VERSION 5.7 ;
  NOWIREEXTENSIONATPIN ON ;
  DIVIDERCHAR "/" ;
  BUSBITCHARS "[]" ;
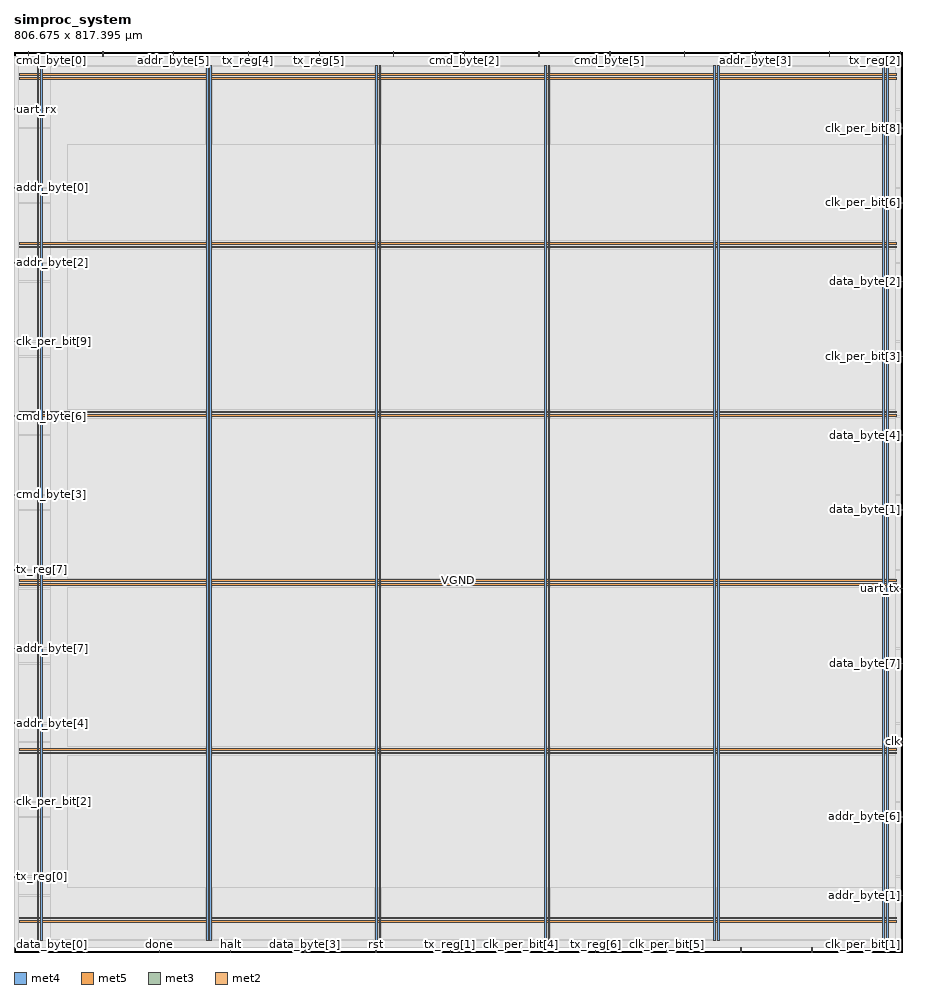
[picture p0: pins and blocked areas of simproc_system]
MACRO simproc_system
  CLASS BLOCK ;
  FOREIGN simproc_system ;
  ORIGIN 0.000 0.000 ;
  SIZE 806.675 BY 817.395 ;
  PIN VGND
    DIRECTION INOUT ;
    USE GROUND ;
    PORT
      LAYER met4 ;
        RECT 24.340 10.640 25.940 805.360 ;
    END
    PORT
      LAYER met4 ;
        RECT 177.940 10.640 179.540 805.360 ;
    END
    PORT
      LAYER met4 ;
        RECT 331.540 10.640 333.140 805.360 ;
    END
    PORT
      LAYER met4 ;
        RECT 485.140 10.640 486.740 805.360 ;
    END
    PORT
      LAYER met4 ;
        RECT 638.740 10.640 640.340 805.360 ;
    END
    PORT
      LAYER met4 ;
        RECT 792.340 10.640 793.940 805.360 ;
    END
    PORT
      LAYER met5 ;
        RECT 5.280 30.030 801.100 31.630 ;
    END
    PORT
      LAYER met5 ;
        RECT 5.280 183.210 801.100 184.810 ;
    END
    PORT
      LAYER met5 ;
        RECT 5.280 336.390 801.100 337.990 ;
    END
    PORT
      LAYER met5 ;
        RECT 5.280 489.570 801.100 491.170 ;
    END
    PORT
      LAYER met5 ;
        RECT 5.280 642.750 801.100 644.350 ;
    END
    PORT
      LAYER met5 ;
        RECT 5.280 795.930 801.100 797.530 ;
    END
  END VGND
  PIN VPWR
    DIRECTION INOUT ;
    USE POWER ;
    PORT
      LAYER met4 ;
        RECT 21.040 10.640 22.640 805.360 ;
    END
    PORT
      LAYER met4 ;
        RECT 174.640 10.640 176.240 805.360 ;
    END
    PORT
      LAYER met4 ;
        RECT 328.240 10.640 329.840 805.360 ;
    END
    PORT
      LAYER met4 ;
        RECT 481.840 10.640 483.440 805.360 ;
    END
    PORT
      LAYER met4 ;
        RECT 635.440 10.640 637.040 805.360 ;
    END
    PORT
      LAYER met4 ;
        RECT 789.040 10.640 790.640 805.360 ;
    END
    PORT
      LAYER met5 ;
        RECT 5.280 26.730 801.100 28.330 ;
    END
    PORT
      LAYER met5 ;
        RECT 5.280 179.910 801.100 181.510 ;
    END
    PORT
      LAYER met5 ;
        RECT 5.280 333.090 801.100 334.690 ;
    END
    PORT
      LAYER met5 ;
        RECT 5.280 486.270 801.100 487.870 ;
    END
    PORT
      LAYER met5 ;
        RECT 5.280 639.450 801.100 641.050 ;
    END
    PORT
      LAYER met5 ;
        RECT 5.280 792.630 801.100 794.230 ;
    END
  END VPWR
  PIN addr_byte[0]
    DIRECTION OUTPUT TRISTATE ;
    USE SIGNAL ;
    ANTENNADIFFAREA 0.795200 ;
    PORT
      LAYER met3 ;
        RECT 0.000 693.640 4.000 694.240 ;
    END
  END addr_byte[0]
  PIN addr_byte[1]
    DIRECTION OUTPUT TRISTATE ;
    USE SIGNAL ;
    ANTENNADIFFAREA 0.445500 ;
    PORT
      LAYER met3 ;
        RECT 802.675 51.040 806.675 51.640 ;
    END
  END addr_byte[1]
  PIN addr_byte[2]
    DIRECTION OUTPUT TRISTATE ;
    USE SIGNAL ;
    ANTENNADIFFAREA 0.795200 ;
    PORT
      LAYER met3 ;
        RECT 0.000 625.640 4.000 626.240 ;
    END
  END addr_byte[2]
  PIN addr_byte[3]
    DIRECTION OUTPUT TRISTATE ;
    USE SIGNAL ;
    ANTENNADIFFAREA 0.795200 ;
    PORT
      LAYER met2 ;
        RECT 673.070 813.395 673.350 817.395 ;
    END
  END addr_byte[3]
  PIN addr_byte[4]
    DIRECTION OUTPUT TRISTATE ;
    USE SIGNAL ;
    ANTENNADIFFAREA 0.795200 ;
    PORT
      LAYER met3 ;
        RECT 0.000 207.440 4.000 208.040 ;
    END
  END addr_byte[4]
  PIN addr_byte[5]
    DIRECTION OUTPUT TRISTATE ;
    USE SIGNAL ;
    ANTENNADIFFAREA 0.795200 ;
    PORT
      LAYER met2 ;
        RECT 144.990 813.395 145.270 817.395 ;
    END
  END addr_byte[5]
  PIN addr_byte[6]
    DIRECTION OUTPUT TRISTATE ;
    USE SIGNAL ;
    ANTENNADIFFAREA 0.795200 ;
    PORT
      LAYER met3 ;
        RECT 802.675 122.440 806.675 123.040 ;
    END
  END addr_byte[6]
  PIN addr_byte[7]
    DIRECTION OUTPUT TRISTATE ;
    USE SIGNAL ;
    ANTENNADIFFAREA 0.795200 ;
    PORT
      LAYER met3 ;
        RECT 0.000 275.440 4.000 276.040 ;
    END
  END addr_byte[7]
  PIN clk
    DIRECTION INPUT ;
    USE SIGNAL ;
    ANTENNAGATEAREA 0.852000 ;
    PORT
      LAYER met3 ;
        RECT 802.675 190.440 806.675 191.040 ;
    END
  END clk
  PIN clk_per_bit[0]
    DIRECTION INPUT ;
    USE SIGNAL ;
    ANTENNAGATEAREA 0.426000 ;
    PORT
      LAYER met2 ;
        RECT 80.590 813.395 80.870 817.395 ;
    END
  END clk_per_bit[0]
  PIN clk_per_bit[1]
    DIRECTION INPUT ;
    USE SIGNAL ;
    ANTENNAGATEAREA 0.742500 ;
    PORT
      LAYER met2 ;
        RECT 792.210 0.000 792.490 4.000 ;
    END
  END clk_per_bit[1]
  PIN clk_per_bit[2]
    DIRECTION INPUT ;
    USE SIGNAL ;
    ANTENNAGATEAREA 0.213000 ;
    PORT
      LAYER met3 ;
        RECT 0.000 136.040 4.000 136.640 ;
    END
  END clk_per_bit[2]
  PIN clk_per_bit[3]
    DIRECTION INPUT ;
    USE SIGNAL ;
    ANTENNAGATEAREA 0.852000 ;
    PORT
      LAYER met3 ;
        RECT 802.675 540.640 806.675 541.240 ;
    END
  END clk_per_bit[3]
  PIN clk_per_bit[4]
    DIRECTION INPUT ;
    USE SIGNAL ;
    ANTENNAGATEAREA 0.426000 ;
    PORT
      LAYER met2 ;
        RECT 460.550 0.000 460.830 4.000 ;
    END
  END clk_per_bit[4]
  PIN clk_per_bit[5]
    DIRECTION INPUT ;
    USE SIGNAL ;
    ANTENNAGATEAREA 0.426000 ;
    PORT
      LAYER met2 ;
        RECT 592.570 0.000 592.850 4.000 ;
    END
  END clk_per_bit[5]
  PIN clk_per_bit[6]
    DIRECTION INPUT ;
    USE SIGNAL ;
    ANTENNAGATEAREA 0.742500 ;
    PORT
      LAYER met3 ;
        RECT 802.675 680.040 806.675 680.640 ;
    END
  END clk_per_bit[6]
  PIN clk_per_bit[7]
    DIRECTION INPUT ;
    USE SIGNAL ;
    ANTENNAGATEAREA 0.742500 ;
    PORT
      LAYER met2 ;
        RECT 660.190 0.000 660.470 4.000 ;
    END
  END clk_per_bit[7]
  PIN clk_per_bit[8]
    DIRECTION INPUT ;
    USE SIGNAL ;
    ANTENNAGATEAREA 0.742500 ;
    PORT
      LAYER met3 ;
        RECT 802.675 748.040 806.675 748.640 ;
    END
  END clk_per_bit[8]
  PIN clk_per_bit[9]
    DIRECTION INPUT ;
    USE SIGNAL ;
    ANTENNAGATEAREA 0.213000 ;
    PORT
      LAYER met3 ;
        RECT 0.000 554.240 4.000 554.840 ;
    END
  END clk_per_bit[9]
  PIN cmd_byte[0]
    DIRECTION OUTPUT TRISTATE ;
    USE SIGNAL ;
    ANTENNADIFFAREA 0.795200 ;
    PORT
      LAYER met2 ;
        RECT 12.970 813.395 13.250 817.395 ;
    END
  END cmd_byte[0]
  PIN cmd_byte[1]
    DIRECTION OUTPUT TRISTATE ;
    USE SIGNAL ;
    ANTENNADIFFAREA 0.795200 ;
    PORT
      LAYER met2 ;
        RECT 608.670 813.395 608.950 817.395 ;
    END
  END cmd_byte[1]
  PIN cmd_byte[2]
    DIRECTION OUTPUT TRISTATE ;
    USE SIGNAL ;
    ANTENNADIFFAREA 0.795200 ;
    PORT
      LAYER met2 ;
        RECT 409.030 813.395 409.310 817.395 ;
    END
  END cmd_byte[2]
  PIN cmd_byte[3]
    DIRECTION OUTPUT TRISTATE ;
    USE SIGNAL ;
    ANTENNADIFFAREA 0.795200 ;
    PORT
      LAYER met3 ;
        RECT 0.000 414.840 4.000 415.440 ;
    END
  END cmd_byte[3]
  PIN cmd_byte[4]
    DIRECTION OUTPUT TRISTATE ;
    USE SIGNAL ;
    ANTENNADIFFAREA 0.795200 ;
    PORT
      LAYER met2 ;
        RECT 344.630 813.395 344.910 817.395 ;
    END
  END cmd_byte[4]
  PIN cmd_byte[5]
    DIRECTION OUTPUT TRISTATE ;
    USE SIGNAL ;
    ANTENNADIFFAREA 0.795200 ;
    PORT
      LAYER met2 ;
        RECT 541.050 813.395 541.330 817.395 ;
    END
  END cmd_byte[5]
  PIN cmd_byte[6]
    DIRECTION OUTPUT TRISTATE ;
    USE SIGNAL ;
    ANTENNADIFFAREA 0.795200 ;
    PORT
      LAYER met3 ;
        RECT 0.000 486.240 4.000 486.840 ;
    END
  END cmd_byte[6]
  PIN cmd_byte[7]
    DIRECTION OUTPUT TRISTATE ;
    USE SIGNAL ;
    ANTENNADIFFAREA 0.795200 ;
    PORT
      LAYER met2 ;
        RECT 64.490 0.000 64.770 4.000 ;
    END
  END cmd_byte[7]
  PIN data_byte[0]
    DIRECTION OUTPUT TRISTATE ;
    USE SIGNAL ;
    ANTENNADIFFAREA 0.795200 ;
    PORT
      LAYER met2 ;
        RECT 0.090 0.000 0.370 4.000 ;
    END
  END data_byte[0]
  PIN data_byte[1]
    DIRECTION OUTPUT TRISTATE ;
    USE SIGNAL ;
    ANTENNADIFFAREA 0.445500 ;
    PORT
      LAYER met3 ;
        RECT 802.675 401.240 806.675 401.840 ;
    END
  END data_byte[1]
  PIN data_byte[2]
    DIRECTION OUTPUT TRISTATE ;
    USE SIGNAL ;
    ANTENNADIFFAREA 0.445500 ;
    PORT
      LAYER met3 ;
        RECT 802.675 608.640 806.675 609.240 ;
    END
  END data_byte[2]
  PIN data_byte[3]
    DIRECTION OUTPUT TRISTATE ;
    USE SIGNAL ;
    ANTENNADIFFAREA 0.795200 ;
    PORT
      LAYER met2 ;
        RECT 264.130 0.000 264.410 4.000 ;
    END
  END data_byte[3]
  PIN data_byte[4]
    DIRECTION OUTPUT TRISTATE ;
    USE SIGNAL ;
    ANTENNADIFFAREA 0.445500 ;
    PORT
      LAYER met3 ;
        RECT 802.675 469.240 806.675 469.840 ;
    END
  END data_byte[4]
  PIN data_byte[5]
    DIRECTION OUTPUT TRISTATE ;
    USE SIGNAL ;
    ANTENNADIFFAREA 0.795200 ;
    PORT
      LAYER met2 ;
        RECT 724.590 0.000 724.870 4.000 ;
    END
  END data_byte[5]
  PIN data_byte[6]
    DIRECTION OUTPUT TRISTATE ;
    USE SIGNAL ;
    ANTENNADIFFAREA 0.795200 ;
    PORT
      LAYER met2 ;
        RECT 476.650 813.395 476.930 817.395 ;
    END
  END data_byte[6]
  PIN data_byte[7]
    DIRECTION OUTPUT TRISTATE ;
    USE SIGNAL ;
    ANTENNADIFFAREA 0.795200 ;
    PORT
      LAYER met3 ;
        RECT 802.675 261.840 806.675 262.440 ;
    END
  END data_byte[7]
  PIN done
    DIRECTION OUTPUT TRISTATE ;
    USE SIGNAL ;
    ANTENNADIFFAREA 0.795200 ;
    PORT
      LAYER met2 ;
        RECT 132.110 0.000 132.390 4.000 ;
    END
  END done
  PIN halt
    DIRECTION OUTPUT TRISTATE ;
    USE SIGNAL ;
    ANTENNADIFFAREA 0.795200 ;
    PORT
      LAYER met2 ;
        RECT 196.510 0.000 196.790 4.000 ;
    END
  END halt
  PIN rst
    DIRECTION INPUT ;
    USE SIGNAL ;
    ANTENNAGATEAREA 0.126000 ;
    PORT
      LAYER met2 ;
        RECT 328.530 0.000 328.810 4.000 ;
    END
  END rst
  PIN tx_reg[0]
    DIRECTION OUTPUT TRISTATE ;
    USE SIGNAL ;
    ANTENNADIFFAREA 0.795200 ;
    PORT
      LAYER met3 ;
        RECT 0.000 68.040 4.000 68.640 ;
    END
  END tx_reg[0]
  PIN tx_reg[1]
    DIRECTION OUTPUT TRISTATE ;
    USE SIGNAL ;
    ANTENNADIFFAREA 0.795200 ;
    PORT
      LAYER met2 ;
        RECT 396.150 0.000 396.430 4.000 ;
    END
  END tx_reg[1]
  PIN tx_reg[2]
    DIRECTION OUTPUT TRISTATE ;
    USE SIGNAL ;
    ANTENNADIFFAREA 0.795200 ;
    PORT
      LAYER met2 ;
        RECT 805.090 813.395 805.370 817.395 ;
    END
  END tx_reg[2]
  PIN tx_reg[3]
    DIRECTION OUTPUT TRISTATE ;
    USE SIGNAL ;
    ANTENNADIFFAREA 0.795200 ;
    PORT
      LAYER met2 ;
        RECT 740.690 813.395 740.970 817.395 ;
    END
  END tx_reg[3]
  PIN tx_reg[4]
    DIRECTION OUTPUT TRISTATE ;
    USE SIGNAL ;
    ANTENNADIFFAREA 0.795200 ;
    PORT
      LAYER met2 ;
        RECT 212.610 813.395 212.890 817.395 ;
    END
  END tx_reg[4]
  PIN tx_reg[5]
    DIRECTION OUTPUT TRISTATE ;
    USE SIGNAL ;
    ANTENNADIFFAREA 0.795200 ;
    PORT
      LAYER met2 ;
        RECT 277.010 813.395 277.290 817.395 ;
    END
  END tx_reg[5]
  PIN tx_reg[6]
    DIRECTION OUTPUT TRISTATE ;
    USE SIGNAL ;
    ANTENNADIFFAREA 0.795200 ;
    PORT
      LAYER met2 ;
        RECT 528.170 0.000 528.450 4.000 ;
    END
  END tx_reg[6]
  PIN tx_reg[7]
    DIRECTION OUTPUT TRISTATE ;
    USE SIGNAL ;
    ANTENNADIFFAREA 0.795200 ;
    PORT
      LAYER met3 ;
        RECT 0.000 346.840 4.000 347.440 ;
    END
  END tx_reg[7]
  PIN uart_rx
    DIRECTION INPUT ;
    USE SIGNAL ;
    ANTENNAGATEAREA 0.196500 ;
    PORT
      LAYER met3 ;
        RECT 0.000 765.040 4.000 765.640 ;
    END
  END uart_rx
  PIN uart_tx
    DIRECTION OUTPUT TRISTATE ;
    USE SIGNAL ;
    ANTENNADIFFAREA 0.795200 ;
    PORT
      LAYER met3 ;
        RECT 802.675 329.840 806.675 330.440 ;
    END
  END uart_tx
  OBS
      LAYER li1 ;
        RECT 5.520 10.795 800.860 805.205 ;
      LAYER met1 ;
        RECT 0.070 10.640 805.390 805.360 ;
      LAYER met2 ;
        RECT 0.100 813.115 12.690 813.690 ;
        RECT 13.530 813.115 80.310 813.690 ;
        RECT 81.150 813.115 144.710 813.690 ;
        RECT 145.550 813.115 212.330 813.690 ;
        RECT 213.170 813.115 276.730 813.690 ;
        RECT 277.570 813.115 344.350 813.690 ;
        RECT 345.190 813.115 408.750 813.690 ;
        RECT 409.590 813.115 476.370 813.690 ;
        RECT 477.210 813.115 540.770 813.690 ;
        RECT 541.610 813.115 608.390 813.690 ;
        RECT 609.230 813.115 672.790 813.690 ;
        RECT 673.630 813.115 740.410 813.690 ;
        RECT 741.250 813.115 804.810 813.690 ;
        RECT 0.100 4.280 805.360 813.115 ;
        RECT 0.650 3.670 64.210 4.280 ;
        RECT 65.050 3.670 131.830 4.280 ;
        RECT 132.670 3.670 196.230 4.280 ;
        RECT 197.070 3.670 263.850 4.280 ;
        RECT 264.690 3.670 328.250 4.280 ;
        RECT 329.090 3.670 395.870 4.280 ;
        RECT 396.710 3.670 460.270 4.280 ;
        RECT 461.110 3.670 527.890 4.280 ;
        RECT 528.730 3.670 592.290 4.280 ;
        RECT 593.130 3.670 659.910 4.280 ;
        RECT 660.750 3.670 724.310 4.280 ;
        RECT 725.150 3.670 791.930 4.280 ;
        RECT 792.770 3.670 805.360 4.280 ;
      LAYER met3 ;
        RECT 4.000 766.040 804.935 805.285 ;
        RECT 4.400 764.640 804.935 766.040 ;
        RECT 4.000 749.040 804.935 764.640 ;
        RECT 4.000 747.640 802.275 749.040 ;
        RECT 4.000 694.640 804.935 747.640 ;
        RECT 4.400 693.240 804.935 694.640 ;
        RECT 4.000 681.040 804.935 693.240 ;
        RECT 4.000 679.640 802.275 681.040 ;
        RECT 4.000 626.640 804.935 679.640 ;
        RECT 4.400 625.240 804.935 626.640 ;
        RECT 4.000 609.640 804.935 625.240 ;
        RECT 4.000 608.240 802.275 609.640 ;
        RECT 4.000 555.240 804.935 608.240 ;
        RECT 4.400 553.840 804.935 555.240 ;
        RECT 4.000 541.640 804.935 553.840 ;
        RECT 4.000 540.240 802.275 541.640 ;
        RECT 4.000 487.240 804.935 540.240 ;
        RECT 4.400 485.840 804.935 487.240 ;
        RECT 4.000 470.240 804.935 485.840 ;
        RECT 4.000 468.840 802.275 470.240 ;
        RECT 4.000 415.840 804.935 468.840 ;
        RECT 4.400 414.440 804.935 415.840 ;
        RECT 4.000 402.240 804.935 414.440 ;
        RECT 4.000 400.840 802.275 402.240 ;
        RECT 4.000 347.840 804.935 400.840 ;
        RECT 4.400 346.440 804.935 347.840 ;
        RECT 4.000 330.840 804.935 346.440 ;
        RECT 4.000 329.440 802.275 330.840 ;
        RECT 4.000 276.440 804.935 329.440 ;
        RECT 4.400 275.040 804.935 276.440 ;
        RECT 4.000 262.840 804.935 275.040 ;
        RECT 4.000 261.440 802.275 262.840 ;
        RECT 4.000 208.440 804.935 261.440 ;
        RECT 4.400 207.040 804.935 208.440 ;
        RECT 4.000 191.440 804.935 207.040 ;
        RECT 4.000 190.040 802.275 191.440 ;
        RECT 4.000 137.040 804.935 190.040 ;
        RECT 4.400 135.640 804.935 137.040 ;
        RECT 4.000 123.440 804.935 135.640 ;
        RECT 4.000 122.040 802.275 123.440 ;
        RECT 4.000 69.040 804.935 122.040 ;
        RECT 4.400 67.640 804.935 69.040 ;
        RECT 4.000 52.040 804.935 67.640 ;
        RECT 4.000 50.640 802.275 52.040 ;
        RECT 4.000 10.715 804.935 50.640 ;
      LAYER met4 ;
        RECT 33.415 11.735 174.240 804.265 ;
        RECT 176.640 11.735 177.540 804.265 ;
        RECT 179.940 11.735 327.840 804.265 ;
        RECT 330.240 11.735 331.140 804.265 ;
        RECT 333.540 11.735 481.440 804.265 ;
        RECT 483.840 11.735 484.740 804.265 ;
        RECT 487.140 11.735 635.040 804.265 ;
        RECT 637.440 11.735 638.340 804.265 ;
        RECT 640.740 11.735 788.640 804.265 ;
        RECT 791.040 11.735 791.940 804.265 ;
        RECT 794.340 11.735 800.530 804.265 ;
      LAYER met5 ;
        RECT 48.420 645.950 800.740 733.500 ;
        RECT 48.420 492.770 800.740 637.850 ;
        RECT 48.420 339.590 800.740 484.670 ;
        RECT 48.420 186.410 800.740 331.490 ;
        RECT 48.420 58.700 800.740 178.310 ;
  END
END simproc_system
END LIBRARY

